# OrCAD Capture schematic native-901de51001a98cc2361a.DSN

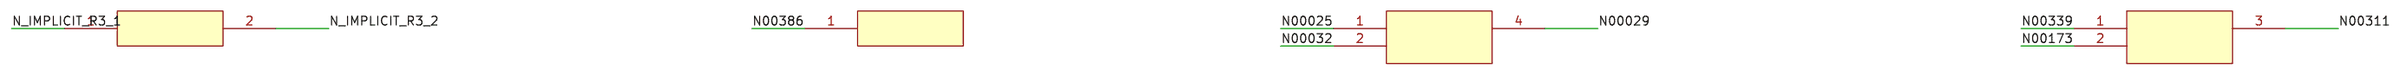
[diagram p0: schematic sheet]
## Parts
R3  6.2K
R9  4.7K
U1  UNKNOWN
U4  UNKNOWN

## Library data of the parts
R3 = OBS_R3
R9 = OBS_R9
U1 = OBS_U1
U4 = OBS_U4

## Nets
N_IMPLICIT_R3_1: R3.1
N_IMPLICIT_R3_2: R3.2

Not connected (* = marked no-connect by the designer): R9 1; U1 1 2 4; U4 1 2 3
